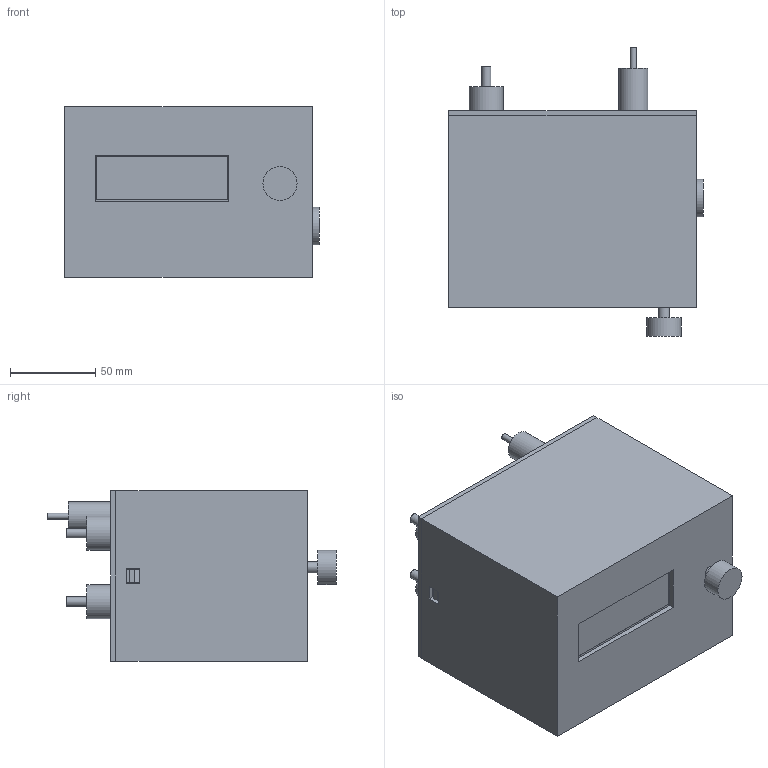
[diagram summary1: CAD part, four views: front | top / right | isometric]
STEP (ISO 10303-21) file: header records copied from the file, then geometry measured from it (millimetres).
FILE_DESCRIPTION(('Open CASCADE Model'),'2;1');
FILE_NAME('Open CASCADE Shape Model','2026-11-04T18:29:48',('Author'),( 'Open CASCADE'),'Open CASCADE STEP processor 7.8','Open CASCADE 7.8' ,'Unknown');
FILE_SCHEMA(('AUTOMOTIVE_DESIGN { 1 0 10303 214 1 1 1 1 }'));
Length unit declared in the file: millimetre
Products named in the file (75): Laboratory_controller_fit_study_02_USB; 01_Pieces_imprimees; 01_Main_shell_with_LCD_and_A_clips; 02_B_removable_carrier_with_clips; 03_Rear_panel_with_latches; 02_Carte_A_reference; PCB_A; A_U1_ENVELOPE; A_U2_ENVELOPE; A_J1_ENVELOPE; A_J6_ENVELOPE; A_J7_ENVELOPE; A_J2_ENVELOPE; A_J3_ENVELOPE; A_J4_ENVELOPE; A_J5_ENVELOPE; A_JP1_ENVELOPE; A_C1_ENVELOPE; A_C2_ENVELOPE; A_C3_ENVELOPE; A_R1_ENVELOPE; A_R2_ENVELOPE; A_R3_ENVELOPE; A_R4_ENVELOPE; A_R5_ENVELOPE; 03_Carte_B_reference; PCB_B; B_U1_ENVELOPE; B_U2_ENVELOPE; B_U3_ENVELOPE; B_U4_ENVELOPE; B_Q1_ENVELOPE; B_F1_ENVELOPE; B_D1_ENVELOPE; B_D2_ENVELOPE; B_J2_ENVELOPE; B_J3_ENVELOPE; B_J4_ENVELOPE; B_J1_ENVELOPE; B_J6_ENVELOPE ...
Assembly tree (74 placements, depth 3):
  Laboratory_controller_fit_study_02_USB
    01_Pieces_imprimees
      01_Main_shell_with_LCD_and_A_clips
      02_B_removable_carrier_with_clips
      03_Rear_panel_with_latches
    02_Carte_A_reference
      PCB_A
      A_U1_ENVELOPE
      A_U2_ENVELOPE
      A_J1_ENVELOPE
      A_J6_ENVELOPE
      A_J7_ENVELOPE
      A_J2_ENVELOPE
      A_J3_ENVELOPE
      A_J4_ENVELOPE
      A_J5_ENVELOPE
      A_JP1_ENVELOPE
      A_C1_ENVELOPE
      A_C2_ENVELOPE
      A_C3_ENVELOPE
      A_R1_ENVELOPE
      A_R2_ENVELOPE
      A_R3_ENVELOPE
      A_R4_ENVELOPE
      A_R5_ENVELOPE
    03_Carte_B_reference
      PCB_B
      B_U1_ENVELOPE
      B_U2_ENVELOPE
      B_U3_ENVELOPE
      B_U4_ENVELOPE
      B_Q1_ENVELOPE
      B_F1_ENVELOPE
      B_D1_ENVELOPE
      B_D2_ENVELOPE
      B_J2_ENVELOPE
      B_J3_ENVELOPE
      B_J4_ENVELOPE
      B_J1_ENVELOPE
      B_J6_ENVELOPE
      B_J7_ENVELOPE
      B_C1_ENVELOPE
      B_C2_ENVELOPE
      B_C3_ENVELOPE
      B_C4_ENVELOPE
      B_C5_ENVELOPE
      B_R1_ENVELOPE
      B_R2_ENVELOPE
      B_R3_ENVELOPE
      B_R4_ENVELOPE
      B_R5_ENVELOPE
      B_R6_ENVELOPE
      B_R7_ENVELOPE
    04_Afficheur_encodeur_reference
      LCD_PCB_98x60_TBD
      LCD_front_bezel_TBD
      LCD_backpack_TBD
      LCD_visible_screen
      Encoder_body_TBD
      Encoder_shaft
Bounding box: 149 x 169 x 100 mm (x, y, z)
Volume: 445900.1 mm3; surface area: 294745.7 mm2
Topology: 68 solids, 68 shells, 687 faces, 1522 edges, 1003 vertices
Faces by surface type: plane 642, cylinder 45
Full cylindrical faces by diameter (mm): 2.2 x12, 3 x3, 3.5 x1, 4.3 x1, 5.5 x2, 6.3 x2, 6.4 x1, 7.2 x1, 8 x1, 12 x6, 12.4 x1, 12.5 x2, 15 x2, 16 x1, 17 x2, 20 x5, 22 x2
Entity records: 40021 total; most frequent: CARTESIAN_POINT 7087, DIRECTION 5718, LINE 3863, VECTOR 3863, ORIENTED_EDGE 3044, PCURVE 3044, DEFINITIONAL_REPRESENTATION 3044, EDGE_CURVE 1522
